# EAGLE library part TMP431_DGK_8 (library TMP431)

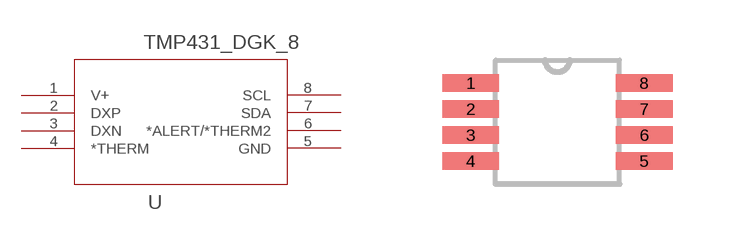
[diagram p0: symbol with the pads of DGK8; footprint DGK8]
Designator prefix U

## TMP431_DGK_8 (DATASHEETURL: http://www.ti.com/lit/gpn/TMP431; DESCRIPTION: +/-1°C Remote and Local Temperature Sensor with Beta, N-Factor and Series-R Correction; FAMILY_NAME: TEMPERATURE SENSOR; GENERIC_PART_NUMBER: TMP431; INDUSTRY_STD_PKG_TYPE: MSOP; MANUFACTURER: Texas Instruments; MANUFACTURER_PART_NUMBER: tmp431_dgk_8; PACKAGE_DESIGNATOR: DGK; PIN_COUNT: 8; VENDOR: Texas Instruments)  [DGK8]
1  V+  pwr
2  DXP  pas
3  DXN  pas
4  *THERM  pas
5  GND  pwr
6  *ALERT/*THERM2  pas
7  SDA  pas
8  SCL  pas

## Footprint DGK8 (pad centres in mm)
smd 1.422 x 0.432: 1 -2.172,0.975; 2 -2.172,0.325; 3 -2.172,-0.325; 4 -2.172,-0.975; 5 2.172,-0.975; 6 2.172,-0.325; 7 2.172,0.325; 8 2.172,0.975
